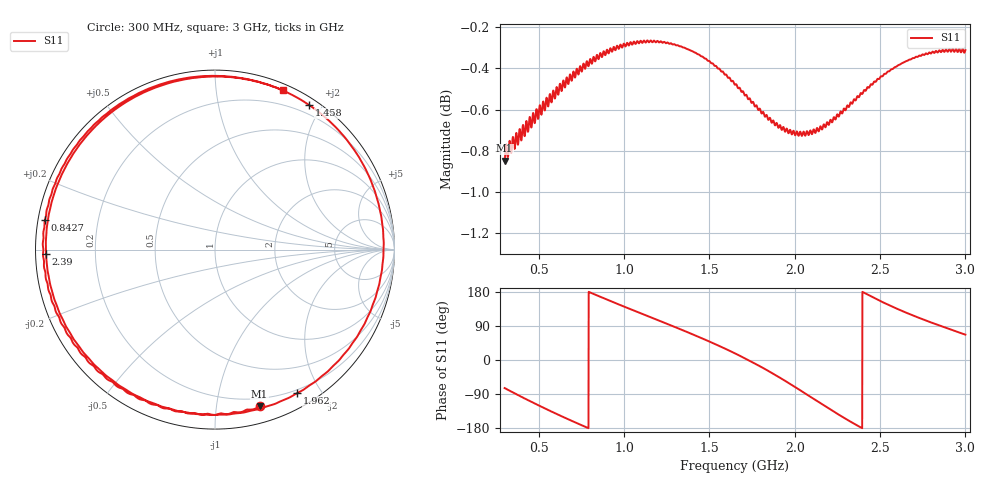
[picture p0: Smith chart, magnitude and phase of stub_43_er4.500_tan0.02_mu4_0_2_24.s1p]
! Chirptenna · simulación 3D de un stub abierto
# HZ S RI R 50
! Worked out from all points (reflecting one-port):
!   2001 points, 300 MHz to 3 GHz, reference 50 ohm
!   lowest |S11| = -0.8 dB at 300 MHz (marker M1), VSWR 20.48, Z = 6.7 - j65.8 ohm
!   phase of S11 starts at -74 deg and turns -579 deg over the sweep
!   S11 on the Smith chart (normalised r, x): 300 MHz: 0.13, -1.32; 842.7 MHz: 0.02, +0.09; 1.458 GHz: 0.09, +1.84; 1.962 GHz: 0.16, -1.72; 2.39 GHz: 0.03, -0.01; 3 GHz: 0.06, +1.51
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3e8  0.2482 -0.8722
3.783e8  -0.0399 -0.9142
4.566e8  -0.3209 -0.8664
5.349e8  -0.5684 -0.7396
6.375e8  -0.8098 -0.486
7.347e8  -0.9339 -0.1861
8.427e8  -0.9481 0.1638
9.75e8  -0.7979 0.5464
1.14915e9  -0.3943 0.8854
1.23015e9  -0.158 0.9561
1.3125e9  0.095 0.9628
1.4583e9  0.5252 0.8052
1.5609e9  0.7687 0.566
1.65e9  0.9027 0.2839
1.7283e9  0.9386 -0.00411
1.8066e9  0.8799 -0.3048
1.8822e9  0.724 -0.5763
1.96185e9  0.4594 -0.7984
1.9875e9  0.3576 -0.849
2.0631e9  0.02 -0.9196
2.1414e9  -0.3359 -0.8587
2.23995e9  -0.7035 -0.6055
2.325e9  -0.8914 -0.2873
2.3898e9  -0.9416 -0.0234
2.5113e9  -0.8503 0.4253
2.6625e9  -0.524 0.8034
2.82045e9  -0.0919 0.9591
3e9  0.378 0.8877
